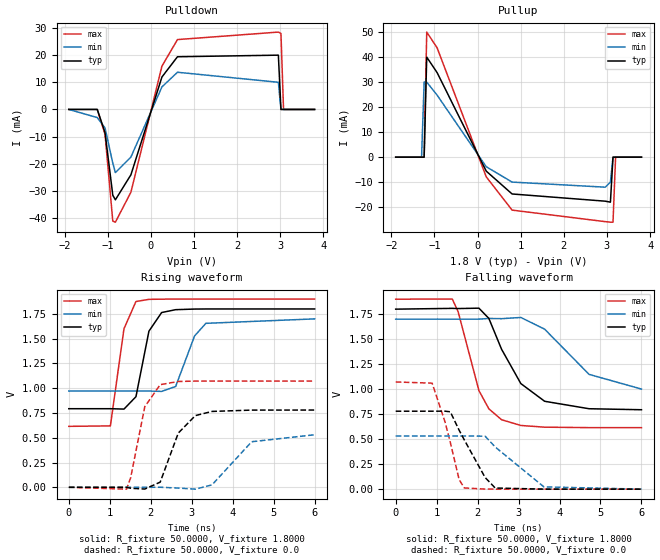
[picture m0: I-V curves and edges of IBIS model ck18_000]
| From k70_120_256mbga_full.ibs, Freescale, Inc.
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|   Model ck18_000
[Model]  ck18_000
Model_type Output
Polarity   Non-Inverting
Enable   Active-High
Vmeas =  0.9000V
Cref =   5.0000pF
Rref =   50.0000
C_comp   2.8000pF   2.5000pF   3.3000pF
[Temperature Range]   25.0000   0.1250k   -40.0000
[Voltage Range]   1.8000V   1.7000V   1.9000V
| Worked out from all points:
|   slope of the pulldown table from 0 to 0.27 V, typ, clamps not added: 22 ohm
|   slope of the pullup table from 0 to 0.27 V, typ, clamps not added: 37.4 ohm
|   rising waveform, R_fixture 50.0000, V_fixture 1.8000: 20-80 % time 293ps typ, 386ps min, 239ps max; typ from 0.793 V to 1.8 V
|   rising waveform, R_fixture 50.0000, V_fixture 0.0: 20-80 % time 465ps typ, 644ps min, 327ps max; typ from 0 V to 0.78 V
|   falling waveform, R_fixture 50.0000, V_fixture 1.8000: 20-80 % time 802ps typ, 1.03ns min, 561ps max; typ from 1.8 V to 0.794 V
|   falling waveform, R_fixture 50.0000, V_fixture 0.0: 20-80 % time 620ps typ, 873ps min, 431ps max; typ from 0.78 V to 0 V
[Pulldown]
|Voltage   I(typ)   I(min)   I(max)
-1.9V     0A         0A         0A
-1.24V    0A         -3mA       0A
-1.06V    -8.58mA    -6.82mA    -9.15mA
-880mV    -31.61mA   -19.8mA    -41.15mA
-820mV    -33.31mA   -23.27mA   -41.55mA
-460mV    -24.09mA   -17.54mA   -30.5mA
260mV     11.96mA    8.306mA    15.96mA
620mV     19.41mA    13.7mA     25.74mA
2.96V     20mA       10mA       28.5mA
3.02V     0A         0A         28mA
3.08V     0A         0A         0A
3.8V      0A         0A         0A
[Pullup]
|Voltage   I(typ)   I(min)   I(max)
-1.9V     0A         0A         0A
-1.3V     0A         0A         0A
-1.24V    0A         30mA       0A
-1.18V    40mA       30mA       50mA
-940mV    33.8mA     24.81mA    43.73mA
200mV     -5.584mA   -3.83mA    -7.872mA
800mV     -14.72mA   -9.966mA   -21.17mA
2.96V     -17.6mA    -12mA      -25.78mA
3.08V     -18mA      -10mA      -26mA
3.14V     0A         0A         -26mA
3.2V      0A         0A         0A
3.8V      0A         0A         0A
[Ramp]
| variable   typ   min   max
dV/dt_r  0.4678/0.4654n   0.3181/0.6401n   0.6434/0.3265n
dV/dt_f  0.6034/0.8016n   0.4195/1.0323n   0.7710/0.5605n
R_load = 50.0000
[Rising Waveform]
R_fixture= 50.0000
V_fixture= 1.8000
V_fixture_min= 1.7000
V_fixture_max= 1.9000
|time   V(typ)   V(min)   V(max)
0s        793.2mV    971.3mV    615.1mV
1.015ns   793.2mV    971.3mV    619.8mV
1.347ns   789.5mV    971.3mV    1.601V
1.639ns   914.4mV    971.3mV    1.875V
1.956ns   1.576V     971.7mV    1.897V
2.266ns   1.764V     967.8mV    1.899V
2.609ns   1.793V     1.018V     1.9V
3.069ns   1.799V     1.527V     1.9V
3.346ns   1.8V       1.655V     1.9V
6ns       1.8V       1.7V       1.9V
[Rising Waveform]
R_fixture= 50.0000
V_fixture= 0.0
|time   V(typ)   V(min)   V(max)
0s        6.58nV     503nV      2.82nV
1.41ns    -459.8uV   906.5nV    -18.83mV
1.511ns   -9.803mV   -58.15nV   98.65mV
1.855ns   -17.69mV   78.77uV    813.9mV
2.231ns   52.06mV    352.2uV    1.036V
2.672ns   547.1mV    -7.903mV   1.068V
3.089ns   723.7mV    -18.96mV   1.072V
3.496ns   765.8mV    24.42mV    1.072V
4.464ns   779.1mV    459.8mV    1.072V
6ns       779.7mV    530.1mV    1.072V
[Falling Waveform]
R_fixture= 50.0000
V_fixture= 1.8000
V_fixture_min= 1.7000
V_fixture_max= 1.9000
|time   V(typ)   V(min)   V(max)
0s        1.8V       1.7V       1.9V
1.382ns   1.808V     1.7V       1.901V
1.524ns   1.806V     1.7V       1.775V
2.032ns   1.81V      1.7V       985.7mV
2.275ns   1.707V     1.707V     803.1mV
2.585ns   1.399V     1.705V     694.3mV
3.055ns   1.056V     1.717V     637mV
3.636ns   878.9mV    1.6V       619.9mV
4.721ns   804.3mV    1.148V     615.4mV
6ns       794.3mV    1.001V     615.1mV
[Falling Waveform]
R_fixture= 50.0000
V_fixture= 0.0
|time   V(typ)   V(min)   V(max)
0s        779.7mV    531.7mV    1.072V
890.4ps   779.7mV    531.7mV    1.06V
1.205ns   780mV      531.7mV    671.2mV
1.333ns   773.8mV    531.7mV    468.8mV
1.549ns   589.4mV    531.7mV    95.18mV
1.676ns   491.7mV    531.7mV    12.06mV
2.183ns   116.8mV    530mV      933.7uV
2.429ns   11.56mV    422mV      402.1uV
3.617ns   269.1uV    23.14mV    16.58uV
6ns       3.865uV    100.8uV    425.2nV
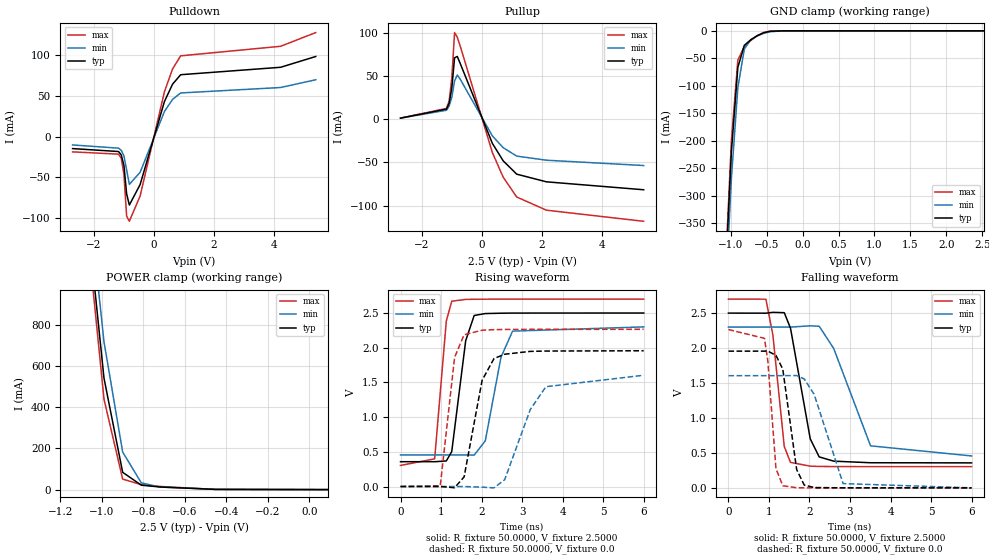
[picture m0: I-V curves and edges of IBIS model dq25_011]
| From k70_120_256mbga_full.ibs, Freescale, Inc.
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|   Model dq25_011
[Model]  dq25_011
Model_type 3-state
Polarity   Non-Inverting
Enable   Active-High
Vmeas =  1.2500V
Cref =   5.0000pF
Rref =   50.0000
C_comp   2.8000pF   2.5000pF   3.3000pF
[Temperature Range]   25.0000   0.1250k   -40.0000
[Voltage Range]   2.5000V   2.3000V   2.7000V
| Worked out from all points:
|   slope of the pulldown table from 0 to 0.375 V, typ, clamps not added: 8.44 ohm
|   slope of the pullup table from 0 to 0.375 V, typ, clamps not added: 13 ohm
|   GND clamp passes 1 mA (typ) near -0.46 V on its own axis
|   POWER clamp passes 1 mA (typ) near -0.45 V on its own axis
|   rising waveform, R_fixture 50.0000, V_fixture 2.5000: 20-80 % time 258ps typ, 353ps min, 178ps max; typ from 0.357 V to 2.5 V
|   rising waveform, R_fixture 50.0000, V_fixture 0.0: 20-80 % time 370ps typ, 630ps min, 226ps max; typ from 0 V to 1.96 V
|   falling waveform, R_fixture 50.0000, V_fixture 2.5000: 20-80 % time 365ps typ, 604ps min, 247ps max; typ from 2.5 V to 0.357 V
|   falling waveform, R_fixture 50.0000, V_fixture 0.0: 20-80 % time 259ps typ, 438ps min, 171ps max; typ from 1.96 V to 0 V
[Pulldown]
|Voltage   I(typ)   I(min)   I(max)
-2.7V     -14.63mA   -10.18mA   -18.66mA
-1.17V    -18.24mA   -14.1mA    -21.43mA
-1.08V    -22.33mA   -16.74mA   -26.5mA
-990mV    -35.4mA    -23.58mA   -46.13mA
-900mV    -70.16mA   -40.97mA   -97.41mA
-810mV    -83.78mA   -58.47mA   -103.7mA
-450mV    -58.61mA   -43.6mA    -72.55mA
360mV     43.1mA     30.89mA    55.11mA
630mV     64.28mA    45.66mA    82.94mA
900mV     75.87mA    53.52mA    98.99mA
4.23V     84.98mA    60.2mA     110.7mA
5.4V      98.2mA     69.7mA     127.5mA
[Pullup]
|Voltage   I(typ)   I(min)   I(max)
-2.7V     1.5mA      1.5mA      1.5mA
-1.17V    11.9mA     10.58mA    12.73mA
-1.08V    18.75mA    15.5mA     21.23mA
-990mV    36.75mA    25.9mA     48.78mA
-900mV    71.45mA    44.56mA    100.8mA
-810mV    73.08mA    51.48mA    95.46mA
-720mV    65.66mA    47.17mA    86.05mA
360mV     -27.87mA   -19.2mA    -38.53mA
720mV     -48.12mA   -32.86mA   -67.1mA
1.17V     -63.57mA   -42.6mA    -90.11mA
2.16V     -72.48mA   -47.39mA   -105.4mA
5.4V      -81.68mA   -53.55mA   -118.3mA
[GND_clamp]
|Voltage   I(typ)   I(min)   I(max)
-2.7V     -6.277A    -6.222A    -6.331A
-1.08V    -464.9mA   -502.8mA   -455.7mA
-990mV    -220.8mA   -269.3mA   -200.2mA
-900mV    -66.44mA   -103.3mA   -53.4mA
-810mV    -26.47mA   -33.22mA   -28.3mA
-720mV    -16.21mA   -16.21mA   -17.69mA
-630mV    -8.78mA    -9.292mA   -8.829mA
-540mV    -3.502mA   -4.566mA   -2.86mA
-450mV    -851.5uA   -1.636mA   -486.2uA
-270mV    -5.965uA   -53.73uA   -641.6nA
2.52V     1.058nA    13.31uA    283.6pA
[POWER_clamp]
|Voltage   I(typ)   I(min)   I(max)
-2.7V     22.73A     22.6A      22.86A
-1.08V    1.419A     1.569A     1.345A
-990mV    540.5mA    717mA      438.5mA
-900mV    83.91mA    182.3mA    51.06mA
-810mV    21.4mA     32.65mA    23.87mA
-720mV    12.71mA    12.3mA     15.28mA
-450mV    963.3uA    1.41mA     776.5uA
90mV      406pA      14.8nA     304.6pA
[Ramp]
| variable   typ   min   max
dV/dt_r  1.1737/0.3695n   0.9616/0.6302n   1.3589/0.2262n
dV/dt_f  1.2856/0.3649n   1.1060/0.6037n   1.4377/0.2473n
R_load = 50.0000
[Rising Waveform]
R_fixture= 50.0000
V_fixture= 2.5000
V_fixture_min= 2.3000
V_fixture_max= 2.7000
|time   V(typ)   V(min)   V(max)
0s        357.4mV    455.5mV    303.8mV
842.5ps   357.4mV    455.5mV    398.7mV
1.13ns    368.4mV    455.5mV    2.385V
1.264ns   503.8mV    455.5mV    2.67V
1.608ns   2.101V     455.6mV    2.696V
1.817ns   2.464V     452.5mV    2.698V
2.092ns   2.492V     657.6mV    2.699V
2.478ns   2.497V     1.861V     2.7V
2.765ns   2.499V     2.239V     2.7V
6ns       2.5V       2.3V       2.7V
[Rising Waveform]
R_fixture= 50.0000
V_fixture= 0.0
|time   V(typ)   V(min)   V(max)
0s        4.777nV    459.2nV    1.549nV
980.5ps   411uV      464.3nV    9.782mV
1.334ns   -17.98mV   709nV      1.86V
1.569ns   138.6mV    -10.9uV    2.187V
2.013ns   1.53V      -9.392mV   2.252V
2.307ns   1.844V     -19.44mV   2.26V
2.57ns    1.906V     98.65mV    2.263V
3.202ns   1.947V     1.109V     2.265V
3.587ns   1.952V     1.438V     2.265V
6ns       1.956V     1.603V     2.265V
[Falling Waveform]
R_fixture= 50.0000
V_fixture= 2.5000
V_fixture_min= 2.3000
V_fixture_max= 2.7000
|time   V(typ)   V(min)   V(max)
0s        2.5V       2.3V       2.7V
924.8ps   2.499V     2.3V       2.699V
1.096ns   2.511V     2.3V       2.19V
1.378ns   2.506V     2.3V       589.9mV
1.532ns   2.283V     2.3V       364mV
2.019ns   700.8mV    2.318V     310.3mV
2.239ns   443.1mV    2.312V     306.6mV
2.597ns   382.1mV    1.995V     304.5mV
3.507ns   359.3mV    601.2mV    303.8mV
6ns       357.4mV    456.6mV    303.8mV
[Falling Waveform]
R_fixture= 50.0000
V_fixture= 0.0
|time   V(typ)   V(min)   V(max)
0s        1.956V     1.605V     2.265V
888.7ps   1.956V     1.605V     2.139V
970.9ps   1.957V     1.605V     1.821V
1.173ns   1.895V     1.605V     274.9mV
1.341ns   1.698V     1.605V     29.96mV
1.683ns   263mV      1.607V     1.635mV
1.87ns    39.59mV    1.558V     799.9uV
2.115ns   4.605mV    1.338V     315.1uV
2.829ns   448.6uV    60.93mV    20.98uV
6ns       98.13nV    15.54uV    211.6nV
